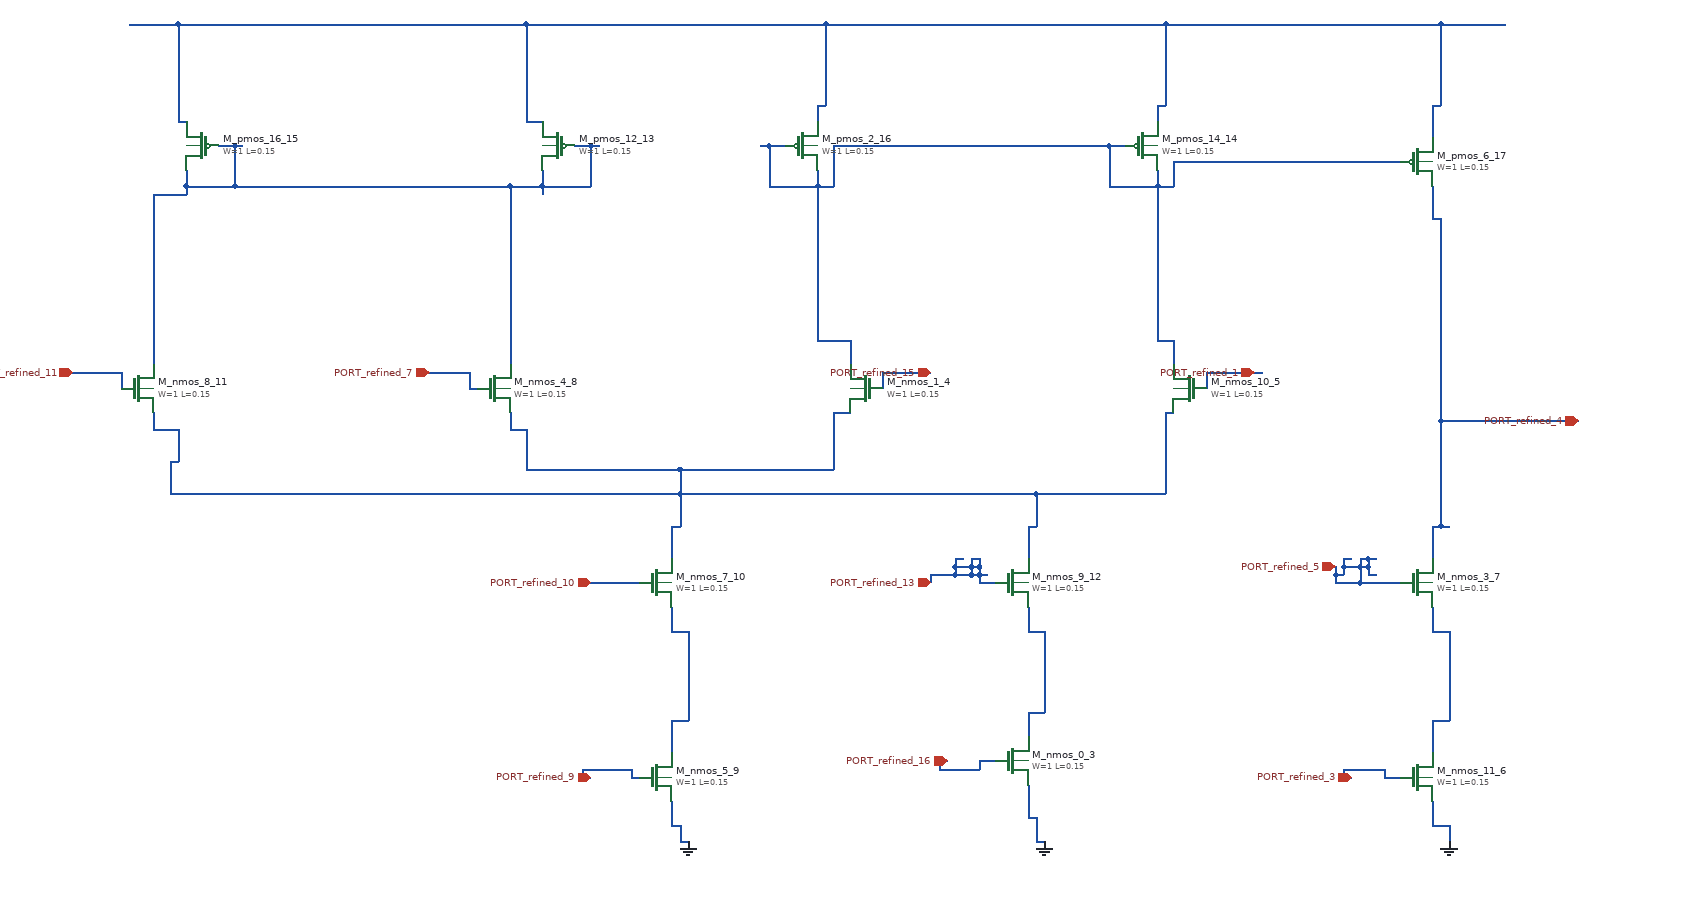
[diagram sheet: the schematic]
v {xschem version=3.4.8 file_version=1.2}
G {}
K {}
V {}
S {}
E {}
C {devices/gnd.sym} 1800 1100 0 0 {name="l_gnd_13_0" lab="GND"}
C {devices/gnd.sym} 860 1100 0 0 {name="l_gnd_15_1" lab="GND"}
C {devices/gnd.sym} 1300 1100 0 0 {name="l_gnd_17_2" lab="GND"}
C {sky130_fd_pr/nfet3_01v8.sym} 1260 1000 0 0 {name="M_nmos_0_3"
W=1
L=0.15
body=GND
nf=1
mult=1
ad="expr('int((@nf + 1)/2) * @W / @nf * 0.29')"
pd="expr('2*int((@nf + 1)/2) * (@W / @nf + 0.29)')"
as="expr('int((@nf + 2)/2) * @W / @nf * 0.29')"
ps="expr('2*int((@nf + 2)/2) * (@W / @nf + 0.29)')"
nrd="expr('0.29 / @W ')" nrs="expr('0.29 / @W ')"
sa=0 sb=0 sd=0
model=nfet_01v8
spiceprefix=X
}
C {sky130_fd_pr/nfet3_01v8.sym} 1080 540 0 1 {name="M_nmos_1_4"
W=1
L=0.15
body=GND
nf=1
mult=1
ad="expr('int((@nf + 1)/2) * @W / @nf * 0.29')"
pd="expr('2*int((@nf + 1)/2) * (@W / @nf + 0.29)')"
as="expr('int((@nf + 2)/2) * @W / @nf * 0.29')"
ps="expr('2*int((@nf + 2)/2) * (@W / @nf + 0.29)')"
nrd="expr('0.29 / @W ')" nrs="expr('0.29 / @W ')"
sa=0 sb=0 sd=0
model=nfet_01v8
spiceprefix=X
}
C {sky130_fd_pr/nfet3_01v8.sym} 1480 540 0 1 {name="M_nmos_10_5"
W=1
L=0.15
body=GND
nf=1
mult=1
ad="expr('int((@nf + 1)/2) * @W / @nf * 0.29')"
pd="expr('2*int((@nf + 1)/2) * (@W / @nf + 0.29)')"
as="expr('int((@nf + 2)/2) * @W / @nf * 0.29')"
ps="expr('2*int((@nf + 2)/2) * (@W / @nf + 0.29)')"
nrd="expr('0.29 / @W ')" nrs="expr('0.29 / @W ')"
sa=0 sb=0 sd=0
model=nfet_01v8
spiceprefix=X
}
C {sky130_fd_pr/nfet3_01v8.sym} 1760 1020 0 0 {name="M_nmos_11_6"
W=1
L=0.15
body=GND
nf=1
mult=1
ad="expr('int((@nf + 1)/2) * @W / @nf * 0.29')"
pd="expr('2*int((@nf + 1)/2) * (@W / @nf + 0.29)')"
as="expr('int((@nf + 2)/2) * @W / @nf * 0.29')"
ps="expr('2*int((@nf + 2)/2) * (@W / @nf + 0.29)')"
nrd="expr('0.29 / @W ')" nrs="expr('0.29 / @W ')"
sa=0 sb=0 sd=0
model=nfet_01v8
spiceprefix=X
}
C {sky130_fd_pr/nfet3_01v8.sym} 1760 780 0 0 {name="M_nmos_3_7"
W=1
L=0.15
body=GND
nf=1
mult=1
ad="expr('int((@nf + 1)/2) * @W / @nf * 0.29')"
pd="expr('2*int((@nf + 1)/2) * (@W / @nf + 0.29)')"
as="expr('int((@nf + 2)/2) * @W / @nf * 0.29')"
ps="expr('2*int((@nf + 2)/2) * (@W / @nf + 0.29)')"
nrd="expr('0.29 / @W ')" nrs="expr('0.29 / @W ')"
sa=0 sb=0 sd=0
model=nfet_01v8
spiceprefix=X
}
C {sky130_fd_pr/nfet3_01v8.sym} 620 540 0 0 {name="M_nmos_4_8"
W=1
L=0.15
body=GND
nf=1
mult=1
ad="expr('int((@nf + 1)/2) * @W / @nf * 0.29')"
pd="expr('2*int((@nf + 1)/2) * (@W / @nf + 0.29)')"
as="expr('int((@nf + 2)/2) * @W / @nf * 0.29')"
ps="expr('2*int((@nf + 2)/2) * (@W / @nf + 0.29)')"
nrd="expr('0.29 / @W ')" nrs="expr('0.29 / @W ')"
sa=0 sb=0 sd=0
model=nfet_01v8
spiceprefix=X
}
C {sky130_fd_pr/nfet3_01v8.sym} 820 1020 0 0 {name="M_nmos_5_9"
W=1
L=0.15
body=GND
nf=1
mult=1
ad="expr('int((@nf + 1)/2) * @W / @nf * 0.29')"
pd="expr('2*int((@nf + 1)/2) * (@W / @nf + 0.29)')"
as="expr('int((@nf + 2)/2) * @W / @nf * 0.29')"
ps="expr('2*int((@nf + 2)/2) * (@W / @nf + 0.29)')"
nrd="expr('0.29 / @W ')" nrs="expr('0.29 / @W ')"
sa=0 sb=0 sd=0
model=nfet_01v8
spiceprefix=X
}
C {sky130_fd_pr/nfet3_01v8.sym} 820 780 0 0 {name="M_nmos_7_10"
W=1
L=0.15
body=GND
nf=1
mult=1
ad="expr('int((@nf + 1)/2) * @W / @nf * 0.29')"
pd="expr('2*int((@nf + 1)/2) * (@W / @nf + 0.29)')"
as="expr('int((@nf + 2)/2) * @W / @nf * 0.29')"
ps="expr('2*int((@nf + 2)/2) * (@W / @nf + 0.29)')"
nrd="expr('0.29 / @W ')" nrs="expr('0.29 / @W ')"
sa=0 sb=0 sd=0
model=nfet_01v8
spiceprefix=X
}
C {sky130_fd_pr/nfet3_01v8.sym} 180 540 0 0 {name="M_nmos_8_11"
W=1
L=0.15
body=GND
nf=1
mult=1
ad="expr('int((@nf + 1)/2) * @W / @nf * 0.29')"
pd="expr('2*int((@nf + 1)/2) * (@W / @nf + 0.29)')"
as="expr('int((@nf + 2)/2) * @W / @nf * 0.29')"
ps="expr('2*int((@nf + 2)/2) * (@W / @nf + 0.29)')"
nrd="expr('0.29 / @W ')" nrs="expr('0.29 / @W ')"
sa=0 sb=0 sd=0
model=nfet_01v8
spiceprefix=X
}
C {sky130_fd_pr/nfet3_01v8.sym} 1260 780 0 0 {name="M_nmos_9_12"
W=1
L=0.15
body=GND
nf=1
mult=1
ad="expr('int((@nf + 1)/2) * @W / @nf * 0.29')"
pd="expr('2*int((@nf + 1)/2) * (@W / @nf + 0.29)')"
as="expr('int((@nf + 2)/2) * @W / @nf * 0.29')"
ps="expr('2*int((@nf + 2)/2) * (@W / @nf + 0.29)')"
nrd="expr('0.29 / @W ')" nrs="expr('0.29 / @W ')"
sa=0 sb=0 sd=0
model=nfet_01v8
spiceprefix=X
}
C {sky130_fd_pr/pfet3_01v8.sym} 700 240 0 1 {name="M_pmos_12_13"
W=1
L=0.15
body=VDD
nf=1
mult=1
ad="expr('int((@nf + 1)/2) * @W / @nf * 0.29')"
pd="expr('2*int((@nf + 1)/2) * (@W / @nf + 0.29)')"
as="expr('int((@nf + 2)/2) * @W / @nf * 0.29')"
ps="expr('2*int((@nf + 2)/2) * (@W / @nf + 0.29)')"
nrd="expr('0.29 / @W ')" nrs="expr('0.29 / @W ')"
sa=0 sb=0 sd=0
model=pfet_01v8
spiceprefix=X
}
C {sky130_fd_pr/pfet3_01v8.sym} 1420 240 0 0 {name="M_pmos_14_14"
W=1
L=0.15
body=VDD
nf=1
mult=1
ad="expr('int((@nf + 1)/2) * @W / @nf * 0.29')"
pd="expr('2*int((@nf + 1)/2) * (@W / @nf + 0.29)')"
as="expr('int((@nf + 2)/2) * @W / @nf * 0.29')"
ps="expr('2*int((@nf + 2)/2) * (@W / @nf + 0.29)')"
nrd="expr('0.29 / @W ')" nrs="expr('0.29 / @W ')"
sa=0 sb=0 sd=0
model=pfet_01v8
spiceprefix=X
}
C {sky130_fd_pr/pfet3_01v8.sym} 260 240 0 1 {name="M_pmos_16_15"
W=1
L=0.15
body=VDD
nf=1
mult=1
ad="expr('int((@nf + 1)/2) * @W / @nf * 0.29')"
pd="expr('2*int((@nf + 1)/2) * (@W / @nf + 0.29)')"
as="expr('int((@nf + 2)/2) * @W / @nf * 0.29')"
ps="expr('2*int((@nf + 2)/2) * (@W / @nf + 0.29)')"
nrd="expr('0.29 / @W ')" nrs="expr('0.29 / @W ')"
sa=0 sb=0 sd=0
model=pfet_01v8
spiceprefix=X
}
C {sky130_fd_pr/pfet3_01v8.sym} 1000 240 0 0 {name="M_pmos_2_16"
W=1
L=0.15
body=VDD
nf=1
mult=1
ad="expr('int((@nf + 1)/2) * @W / @nf * 0.29')"
pd="expr('2*int((@nf + 1)/2) * (@W / @nf + 0.29)')"
as="expr('int((@nf + 2)/2) * @W / @nf * 0.29')"
ps="expr('2*int((@nf + 2)/2) * (@W / @nf + 0.29)')"
nrd="expr('0.29 / @W ')" nrs="expr('0.29 / @W ')"
sa=0 sb=0 sd=0
model=pfet_01v8
spiceprefix=X
}
C {sky130_fd_pr/pfet3_01v8.sym} 1760 260 0 0 {name="M_pmos_6_17"
W=1
L=0.15
body=VDD
nf=1
mult=1
ad="expr('int((@nf + 1)/2) * @W / @nf * 0.29')"
pd="expr('2*int((@nf + 1)/2) * (@W / @nf + 0.29)')"
as="expr('int((@nf + 2)/2) * @W / @nf * 0.29')"
ps="expr('2*int((@nf + 2)/2) * (@W / @nf + 0.29)')"
nrd="expr('0.29 / @W ')" nrs="expr('0.29 / @W ')"
sa=0 sb=0 sd=0
model=pfet_01v8
spiceprefix=X
}
C {devices/ipin.sym} 1160 520 0 0 {name="p_port_21_18" lab="PORT_refined_15"}
C {devices/ipin.sym} 1680 1020 0 0 {name="p_port_23_19" lab="PORT_refined_3"}
C {devices/ipin.sym} 1560 520 0 0 {name="p_port_24_20" lab="PORT_refined_1"}
C {devices/ipin.sym} 740 1020 0 0 {name="p_port_25_21" lab="PORT_refined_9"}
C {devices/ipin.sym} 1660 760 0 0 {name="p_port_26_22" lab="PORT_refined_5"}
C {devices/ipin.sym} 540 520 0 0 {name="p_port_27_23" lab="PORT_refined_7"}
C {devices/ipin.sym} 1960 580 0 0 {name="p_port_28_24" lab="PORT_refined_4"}
C {devices/ipin.sym} 100 520 0 0 {name="p_port_31_25" lab="PORT_refined_11"}
C {devices/ipin.sym} 1180 1000 0 0 {name="p_port_32_26" lab="PORT_refined_16"}
C {devices/ipin.sym} 740 780 0 0 {name="p_port_33_27" lab="PORT_refined_10"}
C {devices/ipin.sym} 1160 780 0 0 {name="p_port_34_28" lab="PORT_refined_13"}
N 850 1100 860 1100 {}
N 1290 1100 1300 1100 {}
N 840 1080 850 1080 {}
N 1780 1080 1800 1080 {}
N 1280 1070 1290 1070 {}
N 840 1080 840 1050 {}
N 850 1100 850 1080 {}
N 1280 1070 1280 1030 {}
N 1290 1100 1290 1070 {}
N 1780 1080 1780 1050 {}
N 1800 1100 1800 1080 {}
N 1500 520 1560 520 {}
N 1560 520 1570 520 {}
N 1500 540 1500 520 {}
N 730 780 740 780 {}
N 740 780 800 780 {}
N 100 520 160 520 {}
N 160 540 160 520 {}
N 1280 940 1300 940 {}
N 1280 840 1300 840 {}
N 1280 970 1280 940 {}
N 1280 840 1280 810 {}
N 1300 940 1300 840 {}
N 1220 780 1240 780 {}
N 1160 770 1190 770 {}
N 1190 770 1210 770 {}
N 1210 770 1220 770 {}
N 1220 770 1230 770 {}
N 1190 760 1210 760 {}
N 1210 760 1220 760 {}
N 1190 750 1200 750 {}
N 1210 750 1220 750 {}
N 1160 780 1160 770 {}
N 1190 770 1190 760 {}
N 1190 760 1190 750 {}
N 1210 770 1210 760 {}
N 1210 760 1210 750 {}
N 1220 780 1220 770 {}
N 1220 770 1220 760 {}
N 1220 760 1220 750 {}
N 230 210 240 210 {}
N 660 210 680 210 {}
N 1020 190 1030 190 {}
N 1440 190 1450 190 {}
N 1780 190 1790 190 {}
N 170 90 230 90 {}
N 230 90 660 90 {}
N 660 90 1030 90 {}
N 1030 90 1450 90 {}
N 1450 90 1790 90 {}
N 1790 90 1870 90 {}
N 230 210 230 90 {}
N 660 210 660 90 {}
N 1020 210 1020 190 {}
N 1030 190 1030 90 {}
N 1440 210 1440 190 {}
N 1450 190 1450 90 {}
N 1780 230 1780 190 {}
N 1790 190 1790 90 {}
N 1100 520 1160 520 {}
N 1100 540 1100 520 {}
N 1170 1010 1220 1010 {}
N 1170 1000 1180 1000 {}
N 1220 1000 1240 1000 {}
N 1170 1010 1170 1000 {}
N 1220 1010 1220 1000 {}
N 200 300 240 300 {}
N 240 290 300 290 {}
N 300 290 640 290 {}
N 640 290 680 290 {}
N 680 290 740 290 {}
N 280 240 300 240 {}
N 300 240 310 240 {}
N 720 240 740 240 {}
N 740 240 750 240 {}
N 200 510 200 300 {}
N 240 300 240 290 {}
N 240 290 240 270 {}
N 300 290 300 240 {}
N 640 510 640 290 {}
N 680 300 680 290 {}
N 680 290 680 270 {}
N 740 290 740 240 {}
N 1020 480 1060 480 {}
N 1440 480 1460 480 {}
N 960 290 1020 290 {}
N 1020 290 1040 290 {}
N 1380 290 1440 290 {}
N 1440 290 1460 290 {}
N 1460 260 1740 260 {}
N 950 240 960 240 {}
N 960 240 980 240 {}
N 1040 240 1380 240 {}
N 1380 240 1400 240 {}
N 960 290 960 240 {}
N 1020 480 1020 290 {}
N 1020 290 1020 270 {}
N 1040 290 1040 240 {}
N 1060 510 1060 480 {}
N 1380 290 1380 240 {}
N 1440 480 1440 290 {}
N 1440 290 1440 270 {}
N 1460 510 1460 480 {}
N 1460 290 1460 260 {}
N 1780 950 1800 950 {}
N 1780 840 1800 840 {}
N 1780 990 1780 950 {}
N 1780 840 1780 810 {}
N 1800 950 1800 840 {}
N 1670 1020 1680 1020 {}
N 1720 1020 1740 1020 {}
N 1670 1010 1720 1010 {}
N 1670 1020 1670 1010 {}
N 1720 1020 1720 1010 {}
N 1780 710 1790 710 {}
N 1790 710 1800 710 {}
N 1790 580 1960 580 {}
N 1780 330 1790 330 {}
N 1780 750 1780 710 {}
N 1780 330 1780 290 {}
N 1790 710 1790 580 {}
N 1790 580 1790 330 {}
N 1660 780 1690 780 {}
N 1690 780 1740 780 {}
N 1660 770 1670 770 {}
N 1700 770 1710 770 {}
N 1670 760 1690 760 {}
N 1690 760 1700 760 {}
N 1670 750 1680 750 {}
N 1690 750 1700 750 {}
N 1700 750 1710 750 {}
N 1660 780 1660 770 {}
N 1660 770 1660 760 {}
N 1670 770 1670 760 {}
N 1670 760 1670 750 {}
N 1690 780 1690 760 {}
N 1690 760 1690 750 {}
N 1700 770 1700 760 {}
N 1700 760 1700 750 {}
N 840 710 850 710 {}
N 1280 710 1290 710 {}
N 220 670 850 670 {}
N 850 670 1290 670 {}
N 1290 670 1450 670 {}
N 660 640 850 640 {}
N 850 640 1040 640 {}
N 220 630 230 630 {}
N 200 590 230 590 {}
N 640 590 660 590 {}
N 1040 570 1060 570 {}
N 1450 570 1460 570 {}
N 200 590 200 570 {}
N 220 670 220 630 {}
N 230 630 230 590 {}
N 640 590 640 570 {}
N 660 640 660 590 {}
N 840 750 840 710 {}
N 850 710 850 670 {}
N 850 670 850 640 {}
N 1040 640 1040 570 {}
N 1280 750 1280 710 {}
N 1290 710 1290 670 {}
N 1450 670 1450 570 {}
N 590 540 600 540 {}
N 540 520 590 520 {}
N 590 540 590 520 {}
N 840 950 860 950 {}
N 840 840 860 840 {}
N 840 990 840 950 {}
N 840 840 840 810 {}
N 860 950 860 840 {}
N 730 1020 740 1020 {}
N 790 1020 800 1020 {}
N 730 1010 790 1010 {}
N 730 1020 730 1010 {}
N 790 1020 790 1010 {}
